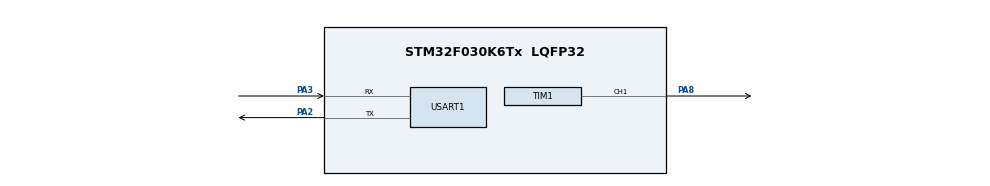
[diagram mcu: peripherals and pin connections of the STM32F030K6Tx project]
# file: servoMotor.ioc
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Mcu.Family=STM32F0
Mcu.Name=STM32F030K6Tx
Mcu.Package=LQFP32
PA13.Mode=Serial_Wire
PA13.Signal=SYS_SWDIO
PA14.Mode=Serial_Wire
PA14.Signal=SYS_SWCLK
PA2.Mode=Asynchronous
PA2.Signal=USART1_TX
PA3.Mode=Asynchronous
PA3.Signal=USART1_RX
PA8.Signal=S_TIM1_CH1
PF0-OSC_IN.Mode=HSE-External-Oscillator
PF0-OSC_IN.Signal=RCC_OSC_IN
PF1-OSC_OUT.Mode=HSE-External-Oscillator
PF1-OSC_OUT.Signal=RCC_OSC_OUT
ProjectManager.HeapSize=0x200
ProjectManager.StackSize=0x400
ProjectManager.TargetToolchain=STM32CubeIDE
RCC.AHBFreq_Value=8000000
RCC.APB1Freq_Value=8000000
RCC.APB1TimFreq_Value=8000000
RCC.HCLKFreq_Value=8000000
RCC.PLLSourceVirtual=RCC_PLLSOURCE_HSE
RCC.SYSCLKFreq_VALUE=8000000
RCC.SYSCLKSource=RCC_SYSCLKSOURCE_HSE
SH.S_TIM1_CH1.0=TIM1_CH1,PWM Generation1 CH1
TIM1.Channel-PWM\ Generation1\ CH1=TIM_CHANNEL_1
USART1.VirtualMode-Asynchronous=VM_ASYNC
VP_TIM1_VS_ClockSourceINT.Mode=Internal
board=custom

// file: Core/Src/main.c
/* USER CODE BEGIN Header */
/**
  ******************************************************************************
  * @file           : main.c
  * @brief          : Main program body
  ******************************************************************************
  * @attention
  *
  * Copyright (c) 2025 STMicroelectronics.
  * All rights reserved.
  *
  * This software is licensed under terms that can be found in the LICENSE file
  * in the root directory of this software component.
  * If no LICENSE file comes with this software, it is provided AS-IS.
  *
  ******************************************************************************
  */
/* USER CODE END Header */
#include "main.h"

TIM_HandleTypeDef htim1;

UART_HandleTypeDef huart1;

void SystemClock_Config(void);
static void MX_GPIO_Init(void);
static void MX_USART1_UART_Init(void);
static void MX_TIM1_Init(void);

int main(void)
{

  /* MCU Configuration--------------------------------------------------------*/

  /* Reset of all peripherals, Initializes the Flash interface and the Systick. */
  HAL_Init();

  /* Configure the system clock */
  SystemClock_Config();

  /* Initialize all configured peripherals */
  MX_GPIO_Init();
  MX_USART1_UART_Init();
  MX_TIM1_Init();

  /* Infinite loop */
  while (1)
  {

  }
}

void SystemClock_Config(void)
{
  RCC_OscInitTypeDef RCC_OscInitStruct = {0};
  RCC_ClkInitTypeDef RCC_ClkInitStruct = {0};
  RCC_PeriphCLKInitTypeDef PeriphClkInit = {0};

  /** Initializes the RCC Oscillators according to the specified parameters
  * in the RCC_OscInitTypeDef structure.
  */
  RCC_OscInitStruct.OscillatorType = RCC_OSCILLATORTYPE_HSI;
  RCC_OscInitStruct.HSIState = RCC_HSI_ON;
  RCC_OscInitStruct.HSICalibrationValue = RCC_HSICALIBRATION_DEFAULT;
  RCC_OscInitStruct.PLL.PLLState = RCC_PLL_NONE;
  if (HAL_RCC_OscConfig(&RCC_OscInitStruct) != HAL_OK)
  {
    Error_Handler();
  }

  /** Initializes the CPU, AHB and APB buses clocks
  */
  RCC_ClkInitStruct.ClockType = RCC_CLOCKTYPE_HCLK|RCC_CLOCKTYPE_SYSCLK
                              |RCC_CLOCKTYPE_PCLK1;
  RCC_ClkInitStruct.SYSCLKSource = RCC_SYSCLKSOURCE_HSI;
  RCC_ClkInitStruct.AHBCLKDivider = RCC_SYSCLK_DIV1;
  RCC_ClkInitStruct.APB1CLKDivider = RCC_HCLK_DIV1;

  if (HAL_RCC_ClockConfig(&RCC_ClkInitStruct, FLASH_LATENCY_0) != HAL_OK)
  {
    Error_Handler();
  }
  PeriphClkInit.PeriphClockSelection = RCC_PERIPHCLK_USART1;
  PeriphClkInit.Usart1ClockSelection = RCC_USART1CLKSOURCE_PCLK1;
  if (HAL_RCCEx_PeriphCLKConfig(&PeriphClkInit) != HAL_OK)
  {
    Error_Handler();
  }
}

static void MX_TIM1_Init(void)
{

  TIM_ClockConfigTypeDef sClockSourceConfig = {0};
  TIM_MasterConfigTypeDef sMasterConfig = {0};
  TIM_OC_InitTypeDef sConfigOC = {0};
  TIM_BreakDeadTimeConfigTypeDef sBreakDeadTimeConfig = {0};

  htim1.Instance = TIM1;
  htim1.Init.Prescaler = 0;
  htim1.Init.CounterMode = TIM_COUNTERMODE_UP;
  htim1.Init.Period = 65535;
  htim1.Init.ClockDivision = TIM_CLOCKDIVISION_DIV1;
  htim1.Init.RepetitionCounter = 0;
  htim1.Init.AutoReloadPreload = TIM_AUTORELOAD_PRELOAD_DISABLE;
  if (HAL_TIM_Base_Init(&htim1) != HAL_OK)
  {
    Error_Handler();
  }
  sClockSourceConfig.ClockSource = TIM_CLOCKSOURCE_INTERNAL;
  if (HAL_TIM_ConfigClockSource(&htim1, &sClockSourceConfig) != HAL_OK)
  {
    Error_Handler();
  }
  if (HAL_TIM_PWM_Init(&htim1) != HAL_OK)
  {
    Error_Handler();
  }
  sMasterConfig.MasterOutputTrigger = TIM_TRGO_RESET;
  sMasterConfig.MasterSlaveMode = TIM_MASTERSLAVEMODE_DISABLE;
  if (HAL_TIMEx_MasterConfigSynchronization(&htim1, &sMasterConfig) != HAL_OK)
  {
    Error_Handler();
  }
  sConfigOC.OCMode = TIM_OCMODE_PWM1;
  sConfigOC.Pulse = 0;
  sConfigOC.OCPolarity = TIM_OCPOLARITY_HIGH;
  sConfigOC.OCNPolarity = TIM_OCNPOLARITY_HIGH;
  sConfigOC.OCFastMode = TIM_OCFAST_DISABLE;
  sConfigOC.OCIdleState = TIM_OCIDLESTATE_RESET;
  sConfigOC.OCNIdleState = TIM_OCNIDLESTATE_RESET;
  if (HAL_TIM_PWM_ConfigChannel(&htim1, &sConfigOC, TIM_CHANNEL_1) != HAL_OK)
  {
    Error_Handler();
  }
  sBreakDeadTimeConfig.OffStateRunMode = TIM_OSSR_DISABLE;
  sBreakDeadTimeConfig.OffStateIDLEMode = TIM_OSSI_DISABLE;
  sBreakDeadTimeConfig.LockLevel = TIM_LOCKLEVEL_OFF;
  sBreakDeadTimeConfig.DeadTime = 0;
  sBreakDeadTimeConfig.BreakState = TIM_BREAK_DISABLE;
  sBreakDeadTimeConfig.BreakPolarity = TIM_BREAKPOLARITY_HIGH;
  sBreakDeadTimeConfig.AutomaticOutput = TIM_AUTOMATICOUTPUT_DISABLE;
  if (HAL_TIMEx_ConfigBreakDeadTime(&htim1, &sBreakDeadTimeConfig) != HAL_OK)
  {
    Error_Handler();
  }
  HAL_TIM_MspPostInit(&htim1);

}

static void MX_USART1_UART_Init(void)
{

  huart1.Instance = USART1;
  huart1.Init.BaudRate = 38400;
  huart1.Init.WordLength = UART_WORDLENGTH_8B;
  huart1.Init.StopBits = UART_STOPBITS_1;
  huart1.Init.Parity = UART_PARITY_NONE;
  huart1.Init.Mode = UART_MODE_TX_RX;
  huart1.Init.HwFlowCtl = UART_HWCONTROL_NONE;
  huart1.Init.OverSampling = UART_OVERSAMPLING_16;
  huart1.Init.OneBitSampling = UART_ONE_BIT_SAMPLE_DISABLE;
  huart1.AdvancedInit.AdvFeatureInit = UART_ADVFEATURE_NO_INIT;
  if (HAL_UART_Init(&huart1) != HAL_OK)
  {
    Error_Handler();
  }

}

static void MX_GPIO_Init(void)
{

  /* GPIO Ports Clock Enable */
  __HAL_RCC_GPIOF_CLK_ENABLE();
  __HAL_RCC_GPIOA_CLK_ENABLE();

}

void Error_Handler(void)
{
  __disable_irq();
  while (1)
  {
  }
}
